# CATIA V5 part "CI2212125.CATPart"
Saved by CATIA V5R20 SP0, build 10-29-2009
Part number: CI2212125
Bounding box of the stored display mesh (mm): x -12 to 12, y -9.46 to 143, z -16.675 to 13.021
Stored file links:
  C:\Users\Raffaele\Desktop\3D X SITO CF\BOLEX\19-INCLINED ASSEMBLY REF_CI\CI2212125.CATPart

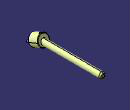
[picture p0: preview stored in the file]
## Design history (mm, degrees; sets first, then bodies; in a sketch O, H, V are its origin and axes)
Set1
  DatumSurface1 to DatumSurface16 "MANIFOLD_SOLID_BREP #383"
  DatumSurface17 to DatumSurface39 "MANIFOLD_SOLID_BREP #1133"
Body1 (main body)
